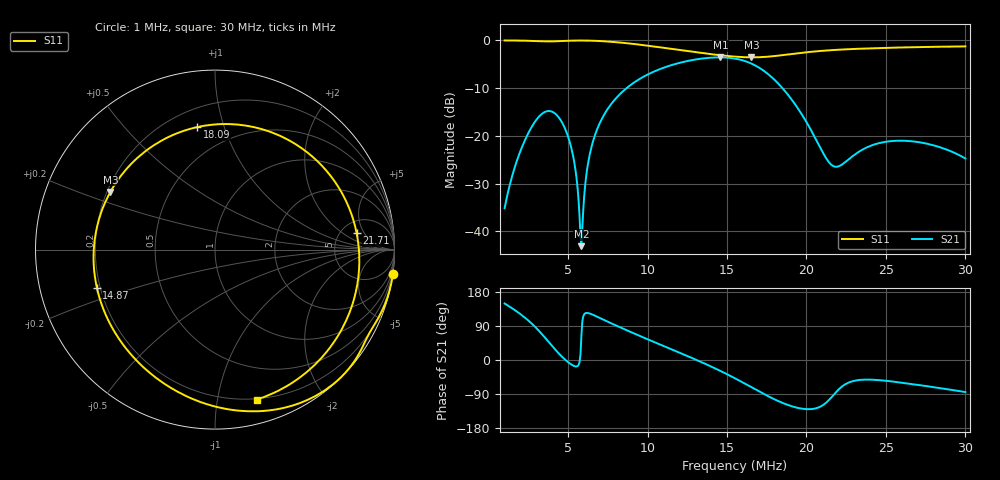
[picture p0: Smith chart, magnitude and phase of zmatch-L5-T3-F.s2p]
# HZ S RI R 50
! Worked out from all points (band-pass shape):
!   505 points, 1 MHz to 30 MHz, reference 50 ohm
!   highest |S21| = -3.54 dB at 14.58 MHz (marker M1); lowest = -43.1 dB at 5.833 MHz (marker M2)
!   |S21| within 3 dB of the highest: 10.38 MHz to 17.39 MHz (7.002 MHz wide, 50.4 % of centre)
!   lowest |S11| = -3.5 dB at 16.54 MHz (marker M3), VSWR 4.98, Z = 10.7 + j12.3 ohm
!   |S11| at or under -10 dB: nowhere
!   S12 and S22 are empty: the file has one direction only
!   S11 on the Smith chart (normalised r, x): 1 MHz: -0, -15; 14.87 MHz: 0.19, -0.15; 18.09 MHz: 0.31, +0.81; 21.71 MHz: 7.01, +3.45; 30 MHz: 0.19, -1.30
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1000000  0.9917 -0.1334  -0.0149 0.00893  0 0  0 0
2438500  0.9403 -0.3205  -0.0286 0.0985  0 0  0 0
3934540  0.8512 -0.4821  0.1391 0.115  0 0  0 0
5142880  0.7739 -0.6258  0.0799 -0.0146  0 0  0 0
5488120  0.7406 -0.6693  0.0388 -0.0119  0 0  0 0
5718280  0.7154 -0.6974  0.014 -0.00121  0 0  0 0
5833360  0.702 -0.711  0.00305 0.00626  0 0  0 0
6293680  0.6432 -0.7615  -0.031 0.047  0 0  0 0
7041700  0.5337 -0.8288  -0.0485 0.1335  0 0  0 0
8480200  0.2961 -0.8966  0.04 0.2939  0 0  0 0
1.066672e7  -0.0807 -0.8495  0.3616 0.335  0 0  0 0
1.285324e7  -0.4257 -0.6295  0.6235 0.0455  0 0  0 0
1.457944e7  -0.6372 -0.2887  0.583 -0.32  0 0  0 0
1.486714e7  -0.6583 -0.212  0.5449 -0.3775  0 0  0 0
1.550008e7  -0.6764 -0.0227  0.4291 -0.4823  0 0  0 0
1.65358e7  -0.5826 0.3218  0.1774 -0.5438  0 0  0 0
1.808938e7  -0.1002 0.6821  -0.102 -0.3581  0 0  0 0
1.906756e7  0.2807 0.6651  -0.1271 -0.2035  0 0  0 0
2.033344e7  0.6333 0.4245  -0.0704 -0.0856  0 0  0 0
2.17144e7  0.7893 0.0907  -0.00138 -0.0479  0 0  0 0
2.51668e7  0.6698 -0.5049  0.0495 -0.0722  0 0  0 0
3.000016e7  0.2316 -0.8355  0.00532 -0.0576  0 0  0 0
